VERSION 5.8 ;
BUSBITCHARS "[]" ;
DIVIDERCHAR "/" ;
UNITS
    DATABASE MICRONS 1000 ;
END UNITS

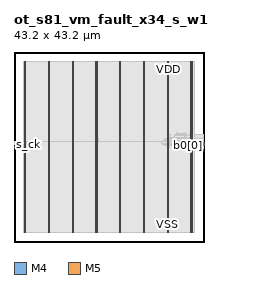
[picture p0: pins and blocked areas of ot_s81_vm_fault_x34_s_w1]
MACRO ot_s81_vm_fault_x34_s_w1
  FOREIGN ot_s81_vm_fault_x34_s_w1 0 0 ;
  CLASS BLOCK ;
  SIZE 43.2 BY 43.2 ;
  PIN b0[0]
    DIRECTION OUTPUT ;
    USE SIGNAL ;
    PORT
      LAYER M4 ;
        RECT  43.116 21.84 43.2 21.864 ;
    END
  END b0[0]
  PIN b0[1]
    DIRECTION OUTPUT ;
    USE SIGNAL ;
    PORT
      LAYER M4 ;
        RECT  43.116 21.936 43.2 21.96 ;
    END
  END b0[1]
  PIN b1[0]
    DIRECTION OUTPUT ;
    USE SIGNAL ;
    PORT
      LAYER M4 ;
        RECT  43.116 22.032 43.2 22.056 ;
    END
  END b1[0]
  PIN b1[1]
    DIRECTION OUTPUT ;
    USE SIGNAL ;
    PORT
      LAYER M4 ;
        RECT  43.116 22.128 43.2 22.152 ;
    END
  END b1[1]
  PIN b2[0]
    DIRECTION OUTPUT ;
    USE SIGNAL ;
    PORT
      LAYER M4 ;
        RECT  43.116 22.224 43.2 22.248 ;
    END
  END b2[0]
  PIN b2[1]
    DIRECTION OUTPUT ;
    USE SIGNAL ;
    PORT
      LAYER M4 ;
        RECT  43.116 22.32 43.2 22.344 ;
    END
  END b2[1]
  PIN bpar[0]
    DIRECTION OUTPUT ;
    USE SIGNAL ;
    PORT
      LAYER M4 ;
        RECT  43.116 22.416 43.2 22.44 ;
    END
  END bpar[0]
  PIN bpar[1]
    DIRECTION OUTPUT ;
    USE SIGNAL ;
    PORT
      LAYER M4 ;
        RECT  43.116 22.512 43.2 22.536 ;
    END
  END bpar[1]
  PIN bpar[2]
    DIRECTION OUTPUT ;
    USE SIGNAL ;
    PORT
      LAYER M4 ;
        RECT  43.116 22.608 43.2 22.632 ;
    END
  END bpar[2]
  PIN s_ck
    DIRECTION INPUT ;
    USE SIGNAL ;
    PORT
      LAYER M4 ;
        RECT  0 22.128 0.084 22.152 ;
    END
  END s_ck
  PIN s_d
    DIRECTION INPUT ;
    USE SIGNAL ;
    PORT
      LAYER M4 ;
        RECT  0 22.224 0.084 22.248 ;
    END
  END s_d
  PIN s_mark
    DIRECTION OUTPUT ;
    USE SIGNAL ;
    PORT
      LAYER M4 ;
        RECT  43.116 22.704 43.2 22.728 ;
    END
  END s_mark
  PIN s_rst_n
    DIRECTION INPUT ;
    USE SIGNAL ;
    PORT
      LAYER M4 ;
        RECT  0 22.32 0.084 22.344 ;
    END
  END s_rst_n
  PIN s_v
    DIRECTION INPUT ;
    USE SIGNAL ;
    PORT
      LAYER M4 ;
        RECT  0 22.416 0.084 22.44 ;
    END
  END s_v
  PIN VDD
    DIRECTION INOUT ;
    USE POWER ;
    PORT
      LAYER M5 ;
        RECT  40.392 2.151 40.512 41.049 ;
        RECT  34.992 2.151 35.112 41.049 ;
        RECT  29.592 2.151 29.712 41.049 ;
        RECT  24.192 2.151 24.312 41.049 ;
        RECT  18.792 2.151 18.912 41.049 ;
        RECT  13.392 2.151 13.512 41.049 ;
        RECT  7.992 2.151 8.112 41.049 ;
        RECT  2.592 2.151 2.712 41.049 ;
    END
  END VDD
  PIN VSS
    DIRECTION INOUT ;
    USE GROUND ;
    PORT
      LAYER M5 ;
        RECT  40.2 2.137 40.32 41.063 ;
        RECT  34.8 2.137 34.92 41.063 ;
        RECT  29.4 2.137 29.52 41.063 ;
        RECT  24 2.137 24.12 41.063 ;
        RECT  18.6 2.137 18.72 41.063 ;
        RECT  13.2 2.137 13.32 41.063 ;
        RECT  7.8 2.137 7.92 41.063 ;
        RECT  2.4 2.137 2.52 41.063 ;
    END
  END VSS
  OBS
    LAYER RVTN ;
     RECT  2.16 2.16 41.04 2.295 ;
     RECT  2.16 2.565 41.04 2.835 ;
     RECT  2.16 3.105 41.04 3.375 ;
     RECT  2.16 3.645 41.04 3.915 ;
     RECT  2.16 4.185 41.04 4.455 ;
     RECT  2.16 4.725 41.04 4.995 ;
     RECT  2.16 5.265 41.04 5.535 ;
     RECT  2.16 5.805 41.04 6.075 ;
     RECT  2.16 6.345 41.04 6.615 ;
     RECT  2.16 6.885 41.04 7.155 ;
     RECT  2.16 7.425 41.04 7.695 ;
     RECT  2.16 7.965 41.04 8.235 ;
     RECT  2.16 8.505 41.04 8.775 ;
     RECT  2.16 9.045 41.04 9.315 ;
     RECT  2.16 9.585 41.04 9.855 ;
     RECT  2.16 10.125 41.04 10.395 ;
     RECT  2.16 10.665 41.04 10.935 ;
     RECT  2.16 11.205 41.04 11.475 ;
     RECT  2.16 11.745 41.04 12.015 ;
     RECT  2.16 12.285 41.04 12.555 ;
     RECT  2.16 12.825 41.04 13.095 ;
     RECT  2.16 13.365 41.04 13.635 ;
     RECT  2.16 13.905 41.04 14.175 ;
     RECT  2.16 14.445 41.04 14.715 ;
     RECT  2.16 14.985 41.04 15.255 ;
     RECT  2.16 15.525 41.04 15.795 ;
     RECT  2.16 16.065 41.04 16.335 ;
     RECT  2.16 16.605 41.04 16.875 ;
     RECT  2.16 17.145 41.04 17.415 ;
     RECT  2.16 17.685 41.04 17.955 ;
     RECT  2.16 18.225 41.04 18.495 ;
     RECT  2.16 18.765 41.04 19.035 ;
     RECT  2.16 19.305 41.04 19.575 ;
     RECT  2.16 19.845 41.04 20.115 ;
     RECT  2.16 20.385 41.04 20.655 ;
     RECT  2.16 20.925 41.04 21.195 ;
     RECT  2.16 21.465 41.04 21.735 ;
     RECT  2.16 22.005 41.04 22.275 ;
     RECT  2.16 22.545 41.04 22.815 ;
     RECT  2.16 23.085 41.04 23.355 ;
     RECT  2.16 23.625 41.04 23.895 ;
     RECT  2.16 24.165 41.04 24.435 ;
     RECT  2.16 24.705 41.04 24.975 ;
     RECT  2.16 25.245 41.04 25.515 ;
     RECT  2.16 25.785 41.04 26.055 ;
     RECT  2.16 26.325 41.04 26.595 ;
     RECT  2.16 26.865 41.04 27.135 ;
     RECT  2.16 27.405 41.04 27.675 ;
     RECT  2.16 27.945 41.04 28.215 ;
     RECT  2.16 28.485 41.04 28.755 ;
     RECT  2.16 29.025 41.04 29.295 ;
     RECT  2.16 29.565 41.04 29.835 ;
     RECT  2.16 30.105 41.04 30.375 ;
     RECT  2.16 30.645 41.04 30.915 ;
     RECT  2.16 31.185 41.04 31.455 ;
     RECT  2.16 31.725 41.04 31.995 ;
     RECT  2.16 32.265 41.04 32.535 ;
     RECT  2.16 32.805 41.04 33.075 ;
     RECT  2.16 33.345 41.04 33.615 ;
     RECT  2.16 33.885 41.04 34.155 ;
     RECT  2.16 34.425 41.04 34.695 ;
     RECT  2.16 34.965 41.04 35.235 ;
     RECT  2.16 35.505 41.04 35.775 ;
     RECT  2.16 36.045 41.04 36.315 ;
     RECT  2.16 36.585 41.04 36.855 ;
     RECT  2.16 37.125 41.04 37.395 ;
     RECT  2.16 37.665 41.04 37.935 ;
     RECT  2.16 38.205 41.04 38.475 ;
     RECT  2.16 38.745 41.04 39.015 ;
     RECT  2.16 39.285 41.04 39.555 ;
     RECT  2.16 39.825 41.04 40.095 ;
     RECT  2.16 40.365 41.04 40.635 ;
     RECT  2.16 40.905 41.04 41.04 ;
    LAYER RVTP ;
     RECT  2.16 2.295 41.04 2.565 ;
     RECT  2.16 2.835 41.04 3.105 ;
     RECT  2.16 3.375 41.04 3.645 ;
     RECT  2.16 3.915 41.04 4.185 ;
     RECT  2.16 4.455 41.04 4.725 ;
     RECT  2.16 4.995 41.04 5.265 ;
     RECT  2.16 5.535 41.04 5.805 ;
     RECT  2.16 6.075 41.04 6.345 ;
     RECT  2.16 6.615 41.04 6.885 ;
     RECT  2.16 7.155 41.04 7.425 ;
     RECT  2.16 7.695 41.04 7.965 ;
     RECT  2.16 8.235 41.04 8.505 ;
     RECT  2.16 8.775 41.04 9.045 ;
     RECT  2.16 9.315 41.04 9.585 ;
     RECT  2.16 9.855 41.04 10.125 ;
     RECT  2.16 10.395 41.04 10.665 ;
     RECT  2.16 10.935 41.04 11.205 ;
     RECT  2.16 11.475 41.04 11.745 ;
     RECT  2.16 12.015 41.04 12.285 ;
     RECT  2.16 12.555 41.04 12.825 ;
     RECT  2.16 13.095 41.04 13.365 ;
     RECT  2.16 13.635 41.04 13.905 ;
     RECT  2.16 14.175 41.04 14.445 ;
     RECT  2.16 14.715 41.04 14.985 ;
     RECT  2.16 15.255 41.04 15.525 ;
     RECT  2.16 15.795 41.04 16.065 ;
     RECT  2.16 16.335 41.04 16.605 ;
     RECT  2.16 16.875 41.04 17.145 ;
     RECT  2.16 17.415 41.04 17.685 ;
     RECT  2.16 17.955 41.04 18.225 ;
     RECT  2.16 18.495 41.04 18.765 ;
     RECT  2.16 19.035 41.04 19.305 ;
     RECT  2.16 19.575 41.04 19.845 ;
     RECT  2.16 20.115 41.04 20.385 ;
     RECT  2.16 20.655 41.04 20.925 ;
     RECT  2.16 21.195 41.04 21.465 ;
     RECT  2.16 21.735 41.04 22.005 ;
     RECT  2.16 22.275 41.04 22.545 ;
     RECT  2.16 22.815 41.04 23.085 ;
     RECT  2.16 23.355 41.04 23.625 ;
     RECT  2.16 23.895 41.04 24.165 ;
     RECT  2.16 24.435 41.04 24.705 ;
     RECT  2.16 24.975 41.04 25.245 ;
     RECT  2.16 25.515 41.04 25.785 ;
     RECT  2.16 26.055 41.04 26.325 ;
     RECT  2.16 26.595 41.04 26.865 ;
     RECT  2.16 27.135 41.04 27.405 ;
     RECT  2.16 27.675 41.04 27.945 ;
     RECT  2.16 28.215 41.04 28.485 ;
     RECT  2.16 28.755 41.04 29.025 ;
     RECT  2.16 29.295 41.04 29.565 ;
     RECT  2.16 29.835 41.04 30.105 ;
     RECT  2.16 30.375 41.04 30.645 ;
     RECT  2.16 30.915 41.04 31.185 ;
     RECT  2.16 31.455 41.04 31.725 ;
     RECT  2.16 31.995 41.04 32.265 ;
     RECT  2.16 32.535 41.04 32.805 ;
     RECT  2.16 33.075 41.04 33.345 ;
     RECT  2.16 33.615 41.04 33.885 ;
     RECT  2.16 34.155 41.04 34.425 ;
     RECT  2.16 34.695 41.04 34.965 ;
     RECT  2.16 35.235 41.04 35.505 ;
     RECT  2.16 35.775 41.04 36.045 ;
     RECT  2.16 36.315 41.04 36.585 ;
     RECT  2.16 36.855 41.04 37.125 ;
     RECT  2.16 37.395 41.04 37.665 ;
     RECT  2.16 37.935 41.04 38.205 ;
     RECT  2.16 38.475 41.04 38.745 ;
     RECT  2.16 39.015 41.04 39.285 ;
     RECT  2.16 39.555 41.04 39.825 ;
     RECT  2.16 40.095 41.04 40.365 ;
     RECT  2.16 40.635 41.04 40.905 ;
    LAYER M1 ;
     RECT  2.16 2.151 41.04 41.049 ;
    LAYER M2 ;
     RECT  2.16 2.151 41.04 41.049 ;
     RECT  41.04 22.446 42.179 22.464 ;
     RECT  41.04 21.276 43.043 21.654 ;
     RECT  41.04 23.526 43.043 24.354 ;
     RECT  43.043 21.276 43.079 21.564 ;
     RECT  43.043 23.526 43.079 24.264 ;
     RECT  43.079 21.546 43.115 21.564 ;
     RECT  43.079 23.796 43.115 24.264 ;
     RECT  43.087 22.446 43.187 22.464 ;
     RECT  43.115 24.246 43.187 24.264 ;
    LAYER M3 ;
     RECT  2.415 2.143 2.505 2.413 ;
     RECT  7.815 2.143 7.905 2.413 ;
     RECT  13.215 2.143 13.305 2.413 ;
     RECT  18.615 2.143 18.705 2.413 ;
     RECT  24.015 2.143 24.105 2.413 ;
     RECT  29.415 2.143 29.505 2.413 ;
     RECT  34.815 2.143 34.905 2.413 ;
     RECT  40.215 2.143 40.305 2.413 ;
     RECT  37.944 20.929 37.962 20.965 ;
     RECT  40.215 2.413 40.497 20.965 ;
     RECT  37.944 20.965 37.998 21.001 ;
     RECT  37.08 20.929 37.098 21.127 ;
     RECT  37.944 21.001 38.034 21.127 ;
     RECT  39.852 20.965 40.497 21.127 ;
     RECT  37.044 21.127 38.034 21.235 ;
     RECT  37.044 21.235 38.178 21.271 ;
     RECT  39.852 21.127 40.734 21.271 ;
     RECT  42.192 21.361 42.21 21.469 ;
     RECT  34.815 2.413 35.097 21.541 ;
     RECT  43.056 21.271 43.074 21.541 ;
     RECT  34.815 21.541 35.226 21.631 ;
     RECT  43.056 21.541 43.11 21.631 ;
     RECT  2.415 2.413 2.697 21.811 ;
     RECT  36.216 21.271 40.734 21.929 ;
     RECT  34.815 21.631 35.334 21.973 ;
     RECT  36.216 21.929 40.698 21.973 ;
     RECT  34.815 21.973 40.698 22.045 ;
     RECT  34.128 22.045 40.698 22.081 ;
     RECT  33.66 22.081 40.698 22.199 ;
     RECT  42.192 21.469 42.246 22.219 ;
     RECT  33.66 22.199 40.59 22.271 ;
     RECT  2.415 21.811 3.114 22.315 ;
     RECT  33.66 22.271 40.554 22.315 ;
     RECT  42.156 22.219 42.246 22.349 ;
     RECT  43.02 21.631 43.11 22.441 ;
     RECT  42.156 22.349 42.174 22.469 ;
     RECT  2.304 22.315 3.114 22.513 ;
     RECT  18.615 2.413 18.897 22.513 ;
     RECT  2.304 22.513 3.294 22.613 ;
     RECT  2.304 22.613 2.697 22.775 ;
     RECT  33.588 22.315 40.554 22.847 ;
     RECT  33.912 22.847 40.554 23.161 ;
     RECT  33.912 23.161 40.698 23.189 ;
     RECT  34.2 23.189 40.698 23.549 ;
     RECT  18.615 22.513 19.17 23.585 ;
     RECT  34.815 23.549 40.698 23.693 ;
     RECT  36.504 23.693 40.698 24.125 ;
     RECT  43.02 22.441 43.182 24.269 ;
     RECT  43.02 24.269 43.038 24.359 ;
     RECT  36.504 24.125 39.15 24.467 ;
     RECT  34.815 23.693 35.622 24.503 ;
     RECT  36.936 24.467 39.15 24.557 ;
     RECT  39.96 24.125 40.698 24.629 ;
     RECT  36.936 24.557 38.07 24.701 ;
     RECT  38.844 24.557 39.15 24.701 ;
     RECT  38.052 24.701 38.07 24.773 ;
     RECT  36.936 24.701 36.954 24.809 ;
     RECT  38.844 24.701 38.862 24.809 ;
     RECT  2.415 22.775 2.697 40.787 ;
     RECT  7.815 2.413 8.097 40.787 ;
     RECT  13.215 2.413 13.497 40.787 ;
     RECT  18.615 23.585 18.897 40.787 ;
     RECT  24.015 2.413 24.297 40.787 ;
     RECT  29.415 2.413 29.697 40.787 ;
     RECT  34.815 24.503 35.097 40.787 ;
     RECT  40.215 24.629 40.497 40.787 ;
     RECT  2.415 40.787 2.505 41.057 ;
     RECT  7.815 40.787 7.905 41.057 ;
     RECT  13.215 40.787 13.305 41.057 ;
     RECT  18.615 40.787 18.705 41.057 ;
     RECT  24.015 40.787 24.105 41.057 ;
     RECT  29.415 40.787 29.505 41.057 ;
     RECT  34.815 40.787 34.905 41.057 ;
     RECT  40.215 40.787 40.305 41.057 ;
    LAYER M4 ;
     RECT  0.06 22.128 0.133 22.44 ;
     RECT  0.133 22.128 0.179 22.824 ;
     RECT  0.179 22.224 2.408 22.824 ;
     RECT  2.408 2.148 2.512 41.052 ;
     RECT  2.512 2.418 2.704 40.782 ;
     RECT  2.704 22.224 2.909 22.824 ;
     RECT  2.909 22.8 7.808 22.824 ;
     RECT  7.808 2.148 7.912 41.052 ;
     RECT  7.912 2.418 8.104 40.782 ;
     RECT  8.104 22.8 13.208 22.824 ;
     RECT  13.208 2.148 13.312 41.052 ;
     RECT  13.312 2.418 13.504 40.782 ;
     RECT  13.504 22.8 18.608 22.824 ;
     RECT  18.608 2.148 18.712 41.052 ;
     RECT  18.712 2.418 18.904 40.782 ;
     RECT  18.904 22.8 24.008 22.824 ;
     RECT  24.008 2.148 24.112 41.052 ;
     RECT  24.112 2.418 24.304 40.782 ;
     RECT  24.304 22.8 29.408 22.824 ;
     RECT  29.408 2.148 29.512 41.052 ;
     RECT  29.512 2.418 29.704 40.782 ;
     RECT  29.704 22.8 33.901 22.824 ;
     RECT  33.901 22.8 34.657 23.16 ;
     RECT  34.657 22.8 34.808 23.304 ;
     RECT  34.808 2.148 34.912 41.052 ;
     RECT  34.912 2.418 35.104 40.782 ;
     RECT  35.104 21.552 35.267 21.576 ;
     RECT  35.104 22.8 35.885 23.304 ;
     RECT  35.885 23.136 37.145 23.304 ;
     RECT  37.145 23.136 37.217 23.16 ;
     RECT  37.069 24.528 38.189 24.552 ;
     RECT  38.077 22.752 38.405 22.776 ;
     RECT  38.725 23.856 39.089 23.88 ;
     RECT  40.208 2.148 40.312 41.052 ;
     RECT  40.312 2.418 40.504 40.782 ;
     RECT  42.145 22.224 42.181 22.248 ;
     RECT  42.181 22.032 42.217 22.248 ;
     RECT  42.217 22.032 43.009 22.344 ;
     RECT  43.009 22.032 43.045 22.728 ;
     RECT  43.045 21.936 43.081 22.728 ;
     RECT  43.081 21.84 43.164 22.728 ;
    LAYER M5 ;
     RECT  2.4 2.137 2.52 2.151 ;
     RECT  7.8 2.137 7.92 2.151 ;
     RECT  13.2 2.137 13.32 2.151 ;
     RECT  18.6 2.137 18.72 2.151 ;
     RECT  24 2.137 24.12 2.151 ;
     RECT  29.4 2.137 29.52 2.151 ;
     RECT  34.8 2.137 34.92 2.151 ;
     RECT  40.2 2.137 40.32 2.151 ;
     RECT  34.8 2.151 35.112 21.541 ;
     RECT  0.144 22.117 0.168 22.835 ;
     RECT  34.8 21.541 35.256 23.171 ;
     RECT  2.4 2.151 2.712 41.049 ;
     RECT  7.8 2.151 8.112 41.049 ;
     RECT  13.2 2.151 13.512 41.049 ;
     RECT  18.6 2.151 18.912 41.049 ;
     RECT  24 2.151 24.312 41.049 ;
     RECT  29.4 2.151 29.712 41.049 ;
     RECT  34.8 23.171 35.112 41.049 ;
     RECT  40.2 2.151 40.512 41.049 ;
     RECT  2.4 41.049 2.52 41.063 ;
     RECT  7.8 41.049 7.92 41.063 ;
     RECT  13.2 41.049 13.32 41.063 ;
     RECT  18.6 41.049 18.72 41.063 ;
     RECT  24 41.049 24.12 41.063 ;
     RECT  29.4 41.049 29.52 41.063 ;
     RECT  34.8 41.049 34.92 41.063 ;
     RECT  40.2 41.049 40.32 41.063 ;
  END
END ot_s81_vm_fault_x34_s_w1
END LIBRARY
